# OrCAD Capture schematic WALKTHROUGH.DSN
size A; title: PSpice Walkthrough; rev: A; company: EMA Design Automation; note: EMA-12345678; note: 225 Tech Park Dr; note: Rochester, NY

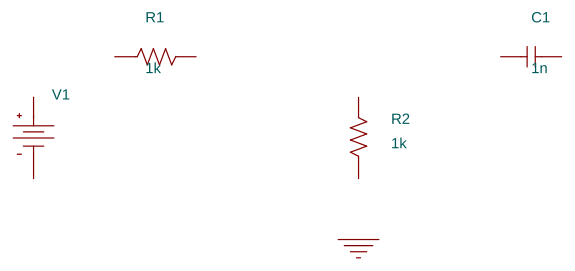
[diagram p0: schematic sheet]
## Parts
C1  1n  [cap196]
R1  1k  [AXRC05]
R2  1k  [AXRC05]
V1  VDC

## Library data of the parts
C1 = C
R1 R2 = R
V1 = VDC

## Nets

Not connected (* = marked no-connect by the designer): C1 1 2; R1 1 2; R2 1 2; V1 0(+) 1(-)
